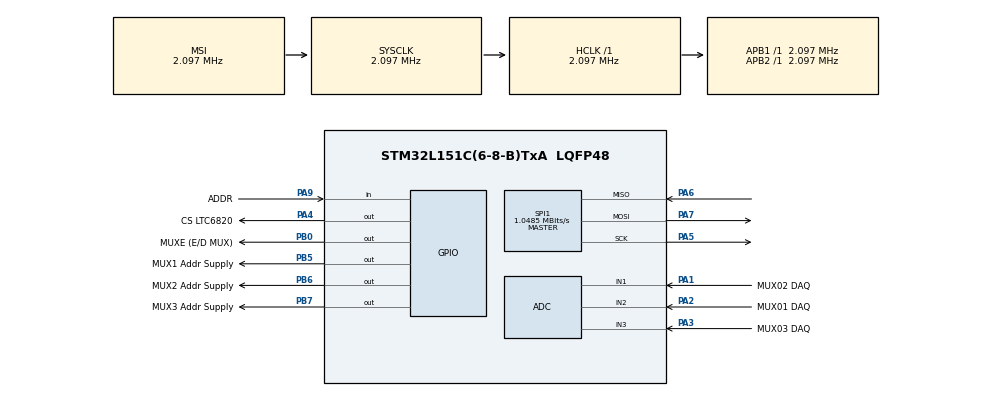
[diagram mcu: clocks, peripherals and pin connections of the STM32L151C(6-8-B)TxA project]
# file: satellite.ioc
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ADC.Channel-0\#ChannelRegularConversion=ADC_CHANNEL_1
ADC.NbrOfConversionFlag=1
ADC.Rank-0\#ChannelRegularConversion=1
ADC.SamplingTime-0\#ChannelRegularConversion=ADC_SAMPLETIME_4CYCLES
Mcu.Family=STM32L1
Mcu.Name=STM32L151C(6-8-B)TxA
Mcu.Package=LQFP48
NVIC.PriorityGroup=NVIC_PRIORITYGROUP_4
PA1.GPIO_Label=MUX02 DAQ
PA1.Mode=IN1
PA1.Signal=ADC_IN1
PA13.GPIO_Label=SW Data In/Out
PA13.Mode=Trace_Asynchronous_SW
PA13.Signal=SYS_JTMS-SWDIO
PA14.GPIO_Label=Serial Wire CLOCK
PA14.Mode=Trace_Asynchronous_SW
PA14.Signal=SYS_JTCK-SWCLK
PA2.GPIO_Label=MUX01 DAQ
PA2.Mode=IN2
PA2.Signal=ADC_IN2
PA3.GPIO_Label=MUX03 DAQ
PA3.Mode=IN3
PA3.Signal=ADC_IN3
PA4.GPIO_Label=CS LTC6820
PA4.Signal=GPIO_Output
PA5.Mode=Full_Duplex_Master
PA5.Signal=SPI1_SCK
PA6.Mode=Full_Duplex_Master
PA6.Signal=SPI1_MISO
PA7.Mode=Full_Duplex_Master
PA7.Signal=SPI1_MOSI
PA9.GPIO_Label=ADDR
PA9.Signal=GPIO_Input
PB0.GPIO_Label=MUXE (E/D MUX)
PB0.Signal=GPIO_Output
PB3.GPIO_Label=Serial Wire OUT
PB3.Mode=Trace_Asynchronous_SW
PB3.Signal=SYS_JTDO-TRACESWO
PB5.GPIO_Label=MUX1 Addr Supply
PB5.Signal=GPIO_Output
PB6.GPIO_Label=MUX2 Addr Supply
PB6.Signal=GPIO_Output
PB7.GPIO_Label=MUX3 Addr Supply
PB7.Signal=GPIO_Output
ProjectManager.HeapSize=0x200
ProjectManager.StackSize=0x400
ProjectManager.TargetToolchain=CMake
RCC.AHBFreq_Value=2097000
RCC.APB1Freq_Value=2097000
RCC.APB2Freq_Value=2097000
RCC.HSE_VALUE=24000000
RCC.HSI_VALUE=16000000
RCC.LSE_VALUE=32768
RCC.MSI_VALUE=2097000
RCC.SYSCLKFreq_VALUE=2097000
RCC.VCOOutputFreq_Value=48000000
SPI1.CalculateBaudRate=1.0485 MBits/s
SPI1.Direction=SPI_DIRECTION_2LINES
SPI1.Mode=SPI_MODE_MASTER
SPI1.VirtualType=VM_MASTER
board=custom

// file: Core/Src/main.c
/* USER CODE BEGIN Header */
/**
  ******************************************************************************
  * @file           : main.c
  * @brief          : Main program body
  ******************************************************************************
  * @attention
  *
  * Copyright (c) 2026 STMicroelectronics.
  * All rights reserved.
  *
  * This software is licensed under terms that can be found in the LICENSE file
  * in the root directory of this software component.
  * If no LICENSE file comes with this software, it is provided AS-IS.
  *
  ******************************************************************************
  */
/* USER CODE END Header */
#include "main.h"

ADC_HandleTypeDef hadc;

SPI_HandleTypeDef hspi1;

void SystemClock_Config(void);
static void MX_GPIO_Init(void);
static void MX_ADC_Init(void);
static void MX_SPI1_Init(void);

int main(void)
{

  /* MCU Configuration--------------------------------------------------------*/

  /* Reset of all peripherals, Initializes the Flash interface and the Systick. */
  HAL_Init();

  /* Configure the system clock */
  SystemClock_Config();

  /* Initialize all configured peripherals */
  MX_GPIO_Init();
  MX_ADC_Init();
  MX_SPI1_Init();

  /* Infinite loop */
  while (1)
  {

  }
}

void SystemClock_Config(void)
{
  RCC_OscInitTypeDef RCC_OscInitStruct = {0};
  RCC_ClkInitTypeDef RCC_ClkInitStruct = {0};

  /** Configure the main internal regulator output voltage
  */
  __HAL_PWR_VOLTAGESCALING_CONFIG(PWR_REGULATOR_VOLTAGE_SCALE1);

  /** Initializes the RCC Oscillators according to the specified parameters
  * in the RCC_OscInitTypeDef structure.
  */
  RCC_OscInitStruct.OscillatorType = RCC_OSCILLATORTYPE_HSI|RCC_OSCILLATORTYPE_MSI;
  RCC_OscInitStruct.HSIState = RCC_HSI_ON;
  RCC_OscInitStruct.HSICalibrationValue = RCC_HSICALIBRATION_DEFAULT;
  RCC_OscInitStruct.MSIState = RCC_MSI_ON;
  RCC_OscInitStruct.MSICalibrationValue = 0;
  RCC_OscInitStruct.MSIClockRange = RCC_MSIRANGE_5;
  RCC_OscInitStruct.PLL.PLLState = RCC_PLL_NONE;
  if (HAL_RCC_OscConfig(&RCC_OscInitStruct) != HAL_OK)
  {
    Error_Handler();
  }

  /** Initializes the CPU, AHB and APB buses clocks
  */
  RCC_ClkInitStruct.ClockType = RCC_CLOCKTYPE_HCLK|RCC_CLOCKTYPE_SYSCLK
                              |RCC_CLOCKTYPE_PCLK1|RCC_CLOCKTYPE_PCLK2;
  RCC_ClkInitStruct.SYSCLKSource = RCC_SYSCLKSOURCE_MSI;
  RCC_ClkInitStruct.AHBCLKDivider = RCC_SYSCLK_DIV1;
  RCC_ClkInitStruct.APB1CLKDivider = RCC_HCLK_DIV1;
  RCC_ClkInitStruct.APB2CLKDivider = RCC_HCLK_DIV1;

  if (HAL_RCC_ClockConfig(&RCC_ClkInitStruct, FLASH_LATENCY_0) != HAL_OK)
  {
    Error_Handler();
  }
}

static void MX_ADC_Init(void)
{

  ADC_ChannelConfTypeDef sConfig = {0};

  /** Configure the global features of the ADC (Clock, Resolution, Data Alignment and number of conversion)
  */
  hadc.Instance = ADC1;
  hadc.Init.ClockPrescaler = ADC_CLOCK_ASYNC_DIV1;
  hadc.Init.Resolution = ADC_RESOLUTION_12B;
  hadc.Init.DataAlign = ADC_DATAALIGN_RIGHT;
  hadc.Init.ScanConvMode = ADC_SCAN_DISABLE;
  hadc.Init.EOCSelection = ADC_EOC_SEQ_CONV;
  hadc.Init.LowPowerAutoWait = ADC_AUTOWAIT_DISABLE;
  hadc.Init.LowPowerAutoPowerOff = ADC_AUTOPOWEROFF_DISABLE;
  hadc.Init.ChannelsBank = ADC_CHANNELS_BANK_A;
  hadc.Init.ContinuousConvMode = DISABLE;
  hadc.Init.NbrOfConversion = 1;
  hadc.Init.DiscontinuousConvMode = DISABLE;
  hadc.Init.ExternalTrigConv = ADC_SOFTWARE_START;
  hadc.Init.ExternalTrigConvEdge = ADC_EXTERNALTRIGCONVEDGE_NONE;
  hadc.Init.DMAContinuousRequests = DISABLE;
  if (HAL_ADC_Init(&hadc) != HAL_OK)
  {
    Error_Handler();
  }

  /** Configure for the selected ADC regular channel its corresponding rank in the sequencer and its sample time.
  */
  sConfig.Channel = ADC_CHANNEL_1;
  sConfig.Rank = ADC_REGULAR_RANK_1;
  sConfig.SamplingTime = ADC_SAMPLETIME_4CYCLES;
  if (HAL_ADC_ConfigChannel(&hadc, &sConfig) != HAL_OK)
  {
    Error_Handler();
  }

}

static void MX_SPI1_Init(void)
{

  /* SPI1 parameter configuration*/
  hspi1.Instance = SPI1;
  hspi1.Init.Mode = SPI_MODE_MASTER;
  hspi1.Init.Direction = SPI_DIRECTION_2LINES;
  hspi1.Init.DataSize = SPI_DATASIZE_8BIT;
  hspi1.Init.CLKPolarity = SPI_POLARITY_LOW;
  hspi1.Init.CLKPhase = SPI_PHASE_1EDGE;
  hspi1.Init.NSS = SPI_NSS_SOFT;
  hspi1.Init.BaudRatePrescaler = SPI_BAUDRATEPRESCALER_2;
  hspi1.Init.FirstBit = SPI_FIRSTBIT_MSB;
  hspi1.Init.TIMode = SPI_TIMODE_DISABLE;
  hspi1.Init.CRCCalculation = SPI_CRCCALCULATION_DISABLE;
  hspi1.Init.CRCPolynomial = 10;
  if (HAL_SPI_Init(&hspi1) != HAL_OK)
  {
    Error_Handler();
  }

}

static void MX_GPIO_Init(void)
{
  GPIO_InitTypeDef GPIO_InitStruct = {0};

  /* GPIO Ports Clock Enable */
  __HAL_RCC_GPIOA_CLK_ENABLE();
  __HAL_RCC_GPIOB_CLK_ENABLE();

  /*Configure GPIO pin Output Level */
  HAL_GPIO_WritePin(CS_LTC6820_GPIO_Port, CS_LTC6820_Pin, GPIO_PIN_RESET);

  /*Configure GPIO pin Output Level */
  HAL_GPIO_WritePin(GPIOB, MUXE_Pin|MUX1_Pin|MUX2_Pin|MUX3_Pin, GPIO_PIN_RESET);

  /*Configure GPIO pin : CS_LTC6820_Pin */
  GPIO_InitStruct.Pin = CS_LTC6820_Pin;
  GPIO_InitStruct.Mode = GPIO_MODE_OUTPUT_PP;
  GPIO_InitStruct.Pull = GPIO_NOPULL;
  GPIO_InitStruct.Speed = GPIO_SPEED_FREQ_LOW;
  HAL_GPIO_Init(CS_LTC6820_GPIO_Port, &GPIO_InitStruct);

  /*Configure GPIO pins : MUXE_Pin MUX1_Pin MUX2_Pin MUX3_Pin */
  GPIO_InitStruct.Pin = MUXE_Pin|MUX1_Pin|MUX2_Pin|MUX3_Pin;
  GPIO_InitStruct.Mode = GPIO_MODE_OUTPUT_PP;
  GPIO_InitStruct.Pull = GPIO_NOPULL;
  GPIO_InitStruct.Speed = GPIO_SPEED_FREQ_LOW;
  HAL_GPIO_Init(GPIOB, &GPIO_InitStruct);

  /*Configure GPIO pin : ADDR_Pin */
  GPIO_InitStruct.Pin = ADDR_Pin;
  GPIO_InitStruct.Mode = GPIO_MODE_INPUT;
  GPIO_InitStruct.Pull = GPIO_NOPULL;
  HAL_GPIO_Init(ADDR_GPIO_Port, &GPIO_InitStruct);

}

void Error_Handler(void)
{
  __disable_irq();
  while (1)
  {
  }
}
